VERSION 5.8 ;
BUSBITCHARS "[]" ;
DIVIDERCHAR "/" ;
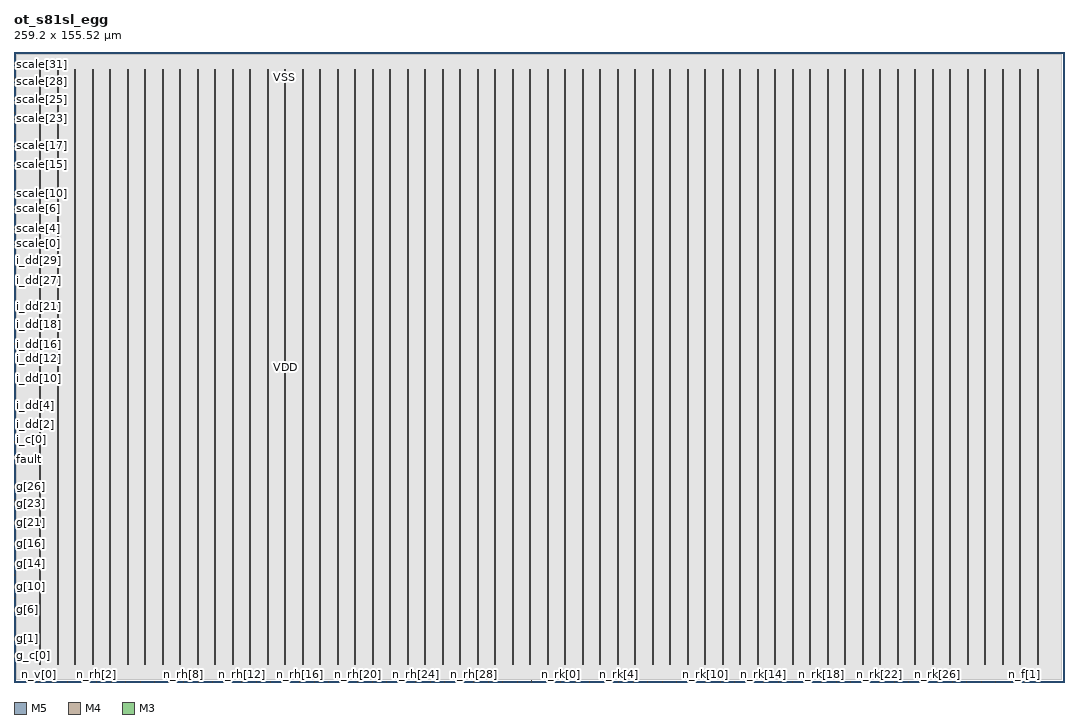
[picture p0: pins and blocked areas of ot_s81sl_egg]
MACRO ot_s81sl_egg
  CLASS BLOCK ;
  ORIGIN 0 0 ;
  FOREIGN ot_s81sl_egg 0 0 ;
  SIZE 259.200 BY 155.520 ;
  SYMMETRY X Y ;
  PIN clk
    DIRECTION INPUT ;
    USE SIGNAL ;
    PORT
      LAYER M5 ;
        RECT 127.7640 0.0000 127.8120 0.4800 ;
    END
  END clk
  PIN fault
    DIRECTION OUTPUT ;
    USE SIGNAL ;
    PORT
      LAYER M4 ;
        RECT 0.0000 54.9120 0.0840 54.9360 ;
    END
  END fault
  PIN g[0]
    DIRECTION OUTPUT ;
    USE SIGNAL ;
    PORT
      LAYER M4 ;
        RECT 0.0000 9.3120 0.0840 9.3360 ;
    END
  END g[0]
  PIN g[10]
    DIRECTION OUTPUT ;
    USE SIGNAL ;
    PORT
      LAYER M4 ;
        RECT 0.0000 23.5200 0.0840 23.5440 ;
    END
  END g[10]
  PIN g[11]
    DIRECTION OUTPUT ;
    USE SIGNAL ;
    PORT
      LAYER M4 ;
        RECT 0.0000 24.9600 0.0840 24.9840 ;
    END
  END g[11]
  PIN g[12]
    DIRECTION OUTPUT ;
    USE SIGNAL ;
    PORT
      LAYER M4 ;
        RECT 0.0000 26.4000 0.0840 26.4240 ;
    END
  END g[12]
  PIN g[13]
    DIRECTION OUTPUT ;
    USE SIGNAL ;
    PORT
      LAYER M4 ;
        RECT 0.0000 27.8400 0.0840 27.8640 ;
    END
  END g[13]
  PIN g[14]
    DIRECTION OUTPUT ;
    USE SIGNAL ;
    PORT
      LAYER M4 ;
        RECT 0.0000 29.2800 0.0840 29.3040 ;
    END
  END g[14]
  PIN g[15]
    DIRECTION OUTPUT ;
    USE SIGNAL ;
    PORT
      LAYER M4 ;
        RECT 0.0000 30.7200 0.0840 30.7440 ;
    END
  END g[15]
  PIN g[16]
    DIRECTION OUTPUT ;
    USE SIGNAL ;
    PORT
      LAYER M4 ;
        RECT 0.0000 32.1600 0.0840 32.1840 ;
    END
  END g[16]
  PIN g[17]
    DIRECTION OUTPUT ;
    USE SIGNAL ;
    PORT
      LAYER M4 ;
        RECT 0.0000 33.5040 0.0840 33.5280 ;
    END
  END g[17]
  PIN g[18]
    DIRECTION OUTPUT ;
    USE SIGNAL ;
    PORT
      LAYER M4 ;
        RECT 0.0000 34.9440 0.0840 34.9680 ;
    END
  END g[18]
  PIN g[19]
    DIRECTION OUTPUT ;
    USE SIGNAL ;
    PORT
      LAYER M4 ;
        RECT 0.0000 36.3840 0.0840 36.4080 ;
    END
  END g[19]
  PIN g[1]
    DIRECTION OUTPUT ;
    USE SIGNAL ;
    PORT
      LAYER M4 ;
        RECT 0.0000 10.7520 0.0840 10.7760 ;
    END
  END g[1]
  PIN g[20]
    DIRECTION OUTPUT ;
    USE SIGNAL ;
    PORT
      LAYER M4 ;
        RECT 0.0000 37.8240 0.0840 37.8480 ;
    END
  END g[20]
  PIN g[21]
    DIRECTION OUTPUT ;
    USE SIGNAL ;
    PORT
      LAYER M4 ;
        RECT 0.0000 39.2640 0.0840 39.2880 ;
    END
  END g[21]
  PIN g[22]
    DIRECTION OUTPUT ;
    USE SIGNAL ;
    PORT
      LAYER M4 ;
        RECT 0.0000 40.7040 0.0840 40.7280 ;
    END
  END g[22]
  PIN g[23]
    DIRECTION OUTPUT ;
    USE SIGNAL ;
    PORT
      LAYER M4 ;
        RECT 0.0000 42.1440 0.0840 42.1680 ;
    END
  END g[23]
  PIN g[24]
    DIRECTION OUTPUT ;
    USE SIGNAL ;
    PORT
      LAYER M4 ;
        RECT 0.0000 43.4880 0.0840 43.5120 ;
    END
  END g[24]
  PIN g[25]
    DIRECTION OUTPUT ;
    USE SIGNAL ;
    PORT
      LAYER M4 ;
        RECT 0.0000 44.9280 0.0840 44.9520 ;
    END
  END g[25]
  PIN g[26]
    DIRECTION OUTPUT ;
    USE SIGNAL ;
    PORT
      LAYER M4 ;
        RECT 0.0000 46.3680 0.0840 46.3920 ;
    END
  END g[26]
  PIN g[27]
    DIRECTION OUTPUT ;
    USE SIGNAL ;
    PORT
      LAYER M4 ;
        RECT 0.0000 47.8080 0.0840 47.8320 ;
    END
  END g[27]
  PIN g[28]
    DIRECTION OUTPUT ;
    USE SIGNAL ;
    PORT
      LAYER M4 ;
        RECT 0.0000 49.2480 0.0840 49.2720 ;
    END
  END g[28]
  PIN g[29]
    DIRECTION OUTPUT ;
    USE SIGNAL ;
    PORT
      LAYER M4 ;
        RECT 0.0000 50.6880 0.0840 50.7120 ;
    END
  END g[29]
  PIN g[2]
    DIRECTION OUTPUT ;
    USE SIGNAL ;
    PORT
      LAYER M4 ;
        RECT 0.0000 12.1920 0.0840 12.2160 ;
    END
  END g[2]
  PIN g[30]
    DIRECTION OUTPUT ;
    USE SIGNAL ;
    PORT
      LAYER M4 ;
        RECT 0.0000 52.0320 0.0840 52.0560 ;
    END
  END g[30]
  PIN g[31]
    DIRECTION OUTPUT ;
    USE SIGNAL ;
    PORT
      LAYER M4 ;
        RECT 0.0000 53.4720 0.0840 53.4960 ;
    END
  END g[31]
  PIN g[3]
    DIRECTION OUTPUT ;
    USE SIGNAL ;
    PORT
      LAYER M4 ;
        RECT 0.0000 13.5360 0.0840 13.5600 ;
    END
  END g[3]
  PIN g[4]
    DIRECTION OUTPUT ;
    USE SIGNAL ;
    PORT
      LAYER M4 ;
        RECT 0.0000 14.9760 0.0840 15.0000 ;
    END
  END g[4]
  PIN g[5]
    DIRECTION OUTPUT ;
    USE SIGNAL ;
    PORT
      LAYER M4 ;
        RECT 0.0000 16.4160 0.0840 16.4400 ;
    END
  END g[5]
  PIN g[6]
    DIRECTION OUTPUT ;
    USE SIGNAL ;
    PORT
      LAYER M4 ;
        RECT 0.0000 17.8560 0.0840 17.8800 ;
    END
  END g[6]
  PIN g[7]
    DIRECTION OUTPUT ;
    USE SIGNAL ;
    PORT
      LAYER M4 ;
        RECT 0.0000 19.2960 0.0840 19.3200 ;
    END
  END g[7]
  PIN g[8]
    DIRECTION OUTPUT ;
    USE SIGNAL ;
    PORT
      LAYER M4 ;
        RECT 0.0000 20.7360 0.0840 20.7600 ;
    END
  END g[8]
  PIN g[9]
    DIRECTION OUTPUT ;
    USE SIGNAL ;
    PORT
      LAYER M4 ;
        RECT 0.0000 22.1760 0.0840 22.2000 ;
    END
  END g[9]
  PIN g_c[0]
    DIRECTION OUTPUT ;
    USE SIGNAL ;
    PORT
      LAYER M4 ;
        RECT 0.0000 6.4320 0.0840 6.4560 ;
    END
  END g_c[0]
  PIN g_c[1]
    DIRECTION OUTPUT ;
    USE SIGNAL ;
    PORT
      LAYER M4 ;
        RECT 0.0000 7.8720 0.0840 7.8960 ;
    END
  END g_c[1]
  PIN g_v
    DIRECTION OUTPUT ;
    USE SIGNAL ;
    PORT
      LAYER M4 ;
        RECT 0.0000 4.9920 0.0840 5.0160 ;
    END
  END g_v
  PIN i_c[0]
    DIRECTION INPUT ;
    USE SIGNAL ;
    PORT
      LAYER M4 ;
        RECT 0.0000 57.7920 0.0840 57.8160 ;
    END
  END i_c[0]
  PIN i_c[1]
    DIRECTION INPUT ;
    USE SIGNAL ;
    PORT
      LAYER M4 ;
        RECT 0.0000 59.2320 0.0840 59.2560 ;
    END
  END i_c[1]
  PIN i_dd[0]
    DIRECTION INPUT ;
    USE SIGNAL ;
    PORT
      LAYER M4 ;
        RECT 0.0000 60.6720 0.0840 60.6960 ;
    END
  END i_dd[0]
  PIN i_dd[10]
    DIRECTION INPUT ;
    USE SIGNAL ;
    PORT
      LAYER M4 ;
        RECT 0.0000 74.8800 0.0840 74.9040 ;
    END
  END i_dd[10]
  PIN i_dd[11]
    DIRECTION INPUT ;
    USE SIGNAL ;
    PORT
      LAYER M4 ;
        RECT 0.0000 76.3200 0.0840 76.3440 ;
    END
  END i_dd[11]
  PIN i_dd[12]
    DIRECTION INPUT ;
    USE SIGNAL ;
    PORT
      LAYER M4 ;
        RECT 0.0000 77.7600 0.0840 77.7840 ;
    END
  END i_dd[12]
  PIN i_dd[13]
    DIRECTION INPUT ;
    USE SIGNAL ;
    PORT
      LAYER M4 ;
        RECT 0.0000 79.2000 0.0840 79.2240 ;
    END
  END i_dd[13]
  PIN i_dd[14]
    DIRECTION INPUT ;
    USE SIGNAL ;
    PORT
      LAYER M4 ;
        RECT 0.0000 80.6400 0.0840 80.6640 ;
    END
  END i_dd[14]
  PIN i_dd[15]
    DIRECTION INPUT ;
    USE SIGNAL ;
    PORT
      LAYER M4 ;
        RECT 0.0000 81.9840 0.0840 82.0080 ;
    END
  END i_dd[15]
  PIN i_dd[16]
    DIRECTION INPUT ;
    USE SIGNAL ;
    PORT
      LAYER M4 ;
        RECT 0.0000 83.4240 0.0840 83.4480 ;
    END
  END i_dd[16]
  PIN i_dd[17]
    DIRECTION INPUT ;
    USE SIGNAL ;
    PORT
      LAYER M4 ;
        RECT 0.0000 84.8640 0.0840 84.8880 ;
    END
  END i_dd[17]
  PIN i_dd[18]
    DIRECTION INPUT ;
    USE SIGNAL ;
    PORT
      LAYER M4 ;
        RECT 0.0000 86.3040 0.0840 86.3280 ;
    END
  END i_dd[18]
  PIN i_dd[19]
    DIRECTION INPUT ;
    USE SIGNAL ;
    PORT
      LAYER M4 ;
        RECT 0.0000 87.7440 0.0840 87.7680 ;
    END
  END i_dd[19]
  PIN i_dd[1]
    DIRECTION INPUT ;
    USE SIGNAL ;
    PORT
      LAYER M4 ;
        RECT 0.0000 62.0160 0.0840 62.0400 ;
    END
  END i_dd[1]
  PIN i_dd[20]
    DIRECTION INPUT ;
    USE SIGNAL ;
    PORT
      LAYER M4 ;
        RECT 0.0000 89.1840 0.0840 89.2080 ;
    END
  END i_dd[20]
  PIN i_dd[21]
    DIRECTION INPUT ;
    USE SIGNAL ;
    PORT
      LAYER M4 ;
        RECT 0.0000 90.6240 0.0840 90.6480 ;
    END
  END i_dd[21]
  PIN i_dd[22]
    DIRECTION INPUT ;
    USE SIGNAL ;
    PORT
      LAYER M4 ;
        RECT 0.0000 91.9680 0.0840 91.9920 ;
    END
  END i_dd[22]
  PIN i_dd[23]
    DIRECTION INPUT ;
    USE SIGNAL ;
    PORT
      LAYER M4 ;
        RECT 0.0000 93.4080 0.0840 93.4320 ;
    END
  END i_dd[23]
  PIN i_dd[24]
    DIRECTION INPUT ;
    USE SIGNAL ;
    PORT
      LAYER M4 ;
        RECT 0.0000 94.8480 0.0840 94.8720 ;
    END
  END i_dd[24]
  PIN i_dd[25]
    DIRECTION INPUT ;
    USE SIGNAL ;
    PORT
      LAYER M4 ;
        RECT 0.0000 96.2880 0.0840 96.3120 ;
    END
  END i_dd[25]
  PIN i_dd[26]
    DIRECTION INPUT ;
    USE SIGNAL ;
    PORT
      LAYER M4 ;
        RECT 0.0000 97.7280 0.0840 97.7520 ;
    END
  END i_dd[26]
  PIN i_dd[27]
    DIRECTION INPUT ;
    USE SIGNAL ;
    PORT
      LAYER M4 ;
        RECT 0.0000 99.1680 0.0840 99.1920 ;
    END
  END i_dd[27]
  PIN i_dd[28]
    DIRECTION INPUT ;
    USE SIGNAL ;
    PORT
      LAYER M4 ;
        RECT 0.0000 100.6080 0.0840 100.6320 ;
    END
  END i_dd[28]
  PIN i_dd[29]
    DIRECTION INPUT ;
    USE SIGNAL ;
    PORT
      LAYER M4 ;
        RECT 0.0000 101.9520 0.0840 101.9760 ;
    END
  END i_dd[29]
  PIN i_dd[2]
    DIRECTION INPUT ;
    USE SIGNAL ;
    PORT
      LAYER M4 ;
        RECT 0.0000 63.4560 0.0840 63.4800 ;
    END
  END i_dd[2]
  PIN i_dd[30]
    DIRECTION INPUT ;
    USE SIGNAL ;
    PORT
      LAYER M4 ;
        RECT 0.0000 103.3920 0.0840 103.4160 ;
    END
  END i_dd[30]
  PIN i_dd[31]
    DIRECTION INPUT ;
    USE SIGNAL ;
    PORT
      LAYER M4 ;
        RECT 0.0000 104.8320 0.0840 104.8560 ;
    END
  END i_dd[31]
  PIN i_dd[3]
    DIRECTION INPUT ;
    USE SIGNAL ;
    PORT
      LAYER M4 ;
        RECT 0.0000 64.8960 0.0840 64.9200 ;
    END
  END i_dd[3]
  PIN i_dd[4]
    DIRECTION INPUT ;
    USE SIGNAL ;
    PORT
      LAYER M4 ;
        RECT 0.0000 66.3360 0.0840 66.3600 ;
    END
  END i_dd[4]
  PIN i_dd[5]
    DIRECTION INPUT ;
    USE SIGNAL ;
    PORT
      LAYER M4 ;
        RECT 0.0000 67.7760 0.0840 67.8000 ;
    END
  END i_dd[5]
  PIN i_dd[6]
    DIRECTION INPUT ;
    USE SIGNAL ;
    PORT
      LAYER M4 ;
        RECT 0.0000 69.2160 0.0840 69.2400 ;
    END
  END i_dd[6]
  PIN i_dd[7]
    DIRECTION INPUT ;
    USE SIGNAL ;
    PORT
      LAYER M4 ;
        RECT 0.0000 70.6560 0.0840 70.6800 ;
    END
  END i_dd[7]
  PIN i_dd[8]
    DIRECTION INPUT ;
    USE SIGNAL ;
    PORT
      LAYER M4 ;
        RECT 0.0000 72.0000 0.0840 72.0240 ;
    END
  END i_dd[8]
  PIN i_dd[9]
    DIRECTION INPUT ;
    USE SIGNAL ;
    PORT
      LAYER M4 ;
        RECT 0.0000 73.4400 0.0840 73.4640 ;
    END
  END i_dd[9]
  PIN i_v
    DIRECTION INPUT ;
    USE SIGNAL ;
    PORT
      LAYER M4 ;
        RECT 0.0000 56.3520 0.0840 56.3760 ;
    END
  END i_v
  PIN n_f[0]
    DIRECTION INPUT ;
    USE SIGNAL ;
    PORT
      LAYER M5 ;
        RECT 9.6960 0.0000 9.7200 0.0840 ;
    END
  END n_f[0]
  PIN n_f[1]
    DIRECTION INPUT ;
    USE SIGNAL ;
    PORT
      LAYER M3 ;
        RECT 249.4800 0.0000 249.4980 0.0380 ;
    END
  END n_f[1]
  PIN n_rh[0]
    DIRECTION INPUT ;
    USE SIGNAL ;
    PORT
      LAYER M3 ;
        RECT 13.2480 0.0000 13.2660 0.0380 ;
    END
  END n_rh[0]
  PIN n_rh[10]
    DIRECTION INPUT ;
    USE SIGNAL ;
    PORT
      LAYER M3 ;
        RECT 49.0320 0.0000 49.0500 0.0380 ;
    END
  END n_rh[10]
  PIN n_rh[11]
    DIRECTION INPUT ;
    USE SIGNAL ;
    PORT
      LAYER M5 ;
        RECT 52.6080 0.0000 52.6320 0.0840 ;
    END
  END n_rh[11]
  PIN n_rh[12]
    DIRECTION INPUT ;
    USE SIGNAL ;
    PORT
      LAYER M3 ;
        RECT 56.2320 0.0000 56.2500 0.0380 ;
    END
  END n_rh[12]
  PIN n_rh[13]
    DIRECTION INPUT ;
    USE SIGNAL ;
    PORT
      LAYER M5 ;
        RECT 59.8080 0.0000 59.8320 0.0840 ;
    END
  END n_rh[13]
  PIN n_rh[14]
    DIRECTION INPUT ;
    USE SIGNAL ;
    PORT
      LAYER M3 ;
        RECT 63.3600 0.0000 63.3780 0.0380 ;
    END
  END n_rh[14]
  PIN n_rh[15]
    DIRECTION INPUT ;
    USE SIGNAL ;
    PORT
      LAYER M5 ;
        RECT 66.9120 0.0000 66.9360 0.0840 ;
    END
  END n_rh[15]
  PIN n_rh[16]
    DIRECTION INPUT ;
    USE SIGNAL ;
    PORT
      LAYER M3 ;
        RECT 70.5600 0.0000 70.5780 0.0380 ;
    END
  END n_rh[16]
  PIN n_rh[17]
    DIRECTION INPUT ;
    USE SIGNAL ;
    PORT
      LAYER M5 ;
        RECT 74.1120 0.0000 74.1360 0.0840 ;
    END
  END n_rh[17]
  PIN n_rh[18]
    DIRECTION INPUT ;
    USE SIGNAL ;
    PORT
      LAYER M3 ;
        RECT 77.6880 0.0000 77.7060 0.0380 ;
    END
  END n_rh[18]
  PIN n_rh[19]
    DIRECTION INPUT ;
    USE SIGNAL ;
    PORT
      LAYER M5 ;
        RECT 81.3120 0.0000 81.3360 0.0840 ;
    END
  END n_rh[19]
  PIN n_rh[1]
    DIRECTION INPUT ;
    USE SIGNAL ;
    PORT
      LAYER M5 ;
        RECT 16.8000 0.0000 16.8240 0.0840 ;
    END
  END n_rh[1]
  PIN n_rh[20]
    DIRECTION INPUT ;
    USE SIGNAL ;
    PORT
      LAYER M3 ;
        RECT 84.8160 0.0000 84.8340 0.0380 ;
    END
  END n_rh[20]
  PIN n_rh[21]
    DIRECTION INPUT ;
    USE SIGNAL ;
    PORT
      LAYER M5 ;
        RECT 88.4160 0.0000 88.4400 0.0840 ;
    END
  END n_rh[21]
  PIN n_rh[22]
    DIRECTION INPUT ;
    USE SIGNAL ;
    PORT
      LAYER M3 ;
        RECT 92.0160 0.0000 92.0340 0.0380 ;
    END
  END n_rh[22]
  PIN n_rh[23]
    DIRECTION INPUT ;
    USE SIGNAL ;
    PORT
      LAYER M5 ;
        RECT 95.6160 0.0000 95.6400 0.0840 ;
    END
  END n_rh[23]
  PIN n_rh[24]
    DIRECTION INPUT ;
    USE SIGNAL ;
    PORT
      LAYER M3 ;
        RECT 99.1440 0.0000 99.1620 0.0380 ;
    END
  END n_rh[24]
  PIN n_rh[25]
    DIRECTION INPUT ;
    USE SIGNAL ;
    PORT
      LAYER M5 ;
        RECT 102.7200 0.0000 102.7440 0.0840 ;
    END
  END n_rh[25]
  PIN n_rh[26]
    DIRECTION INPUT ;
    USE SIGNAL ;
    PORT
      LAYER M3 ;
        RECT 106.3440 0.0000 106.3620 0.0380 ;
    END
  END n_rh[26]
  PIN n_rh[27]
    DIRECTION INPUT ;
    USE SIGNAL ;
    PORT
      LAYER M5 ;
        RECT 109.9200 0.0000 109.9440 0.0840 ;
    END
  END n_rh[27]
  PIN n_rh[28]
    DIRECTION INPUT ;
    USE SIGNAL ;
    PORT
      LAYER M3 ;
        RECT 113.4720 0.0000 113.4900 0.0380 ;
    END
  END n_rh[28]
  PIN n_rh[29]
    DIRECTION INPUT ;
    USE SIGNAL ;
    PORT
      LAYER M5 ;
        RECT 117.0240 0.0000 117.0480 0.0840 ;
    END
  END n_rh[29]
  PIN n_rh[2]
    DIRECTION INPUT ;
    USE SIGNAL ;
    PORT
      LAYER M3 ;
        RECT 20.4480 0.0000 20.4660 0.0380 ;
    END
  END n_rh[2]
  PIN n_rh[30]
    DIRECTION INPUT ;
    USE SIGNAL ;
    PORT
      LAYER M3 ;
        RECT 120.6720 0.0000 120.6900 0.0380 ;
    END
  END n_rh[30]
  PIN n_rh[31]
    DIRECTION INPUT ;
    USE SIGNAL ;
    PORT
      LAYER M5 ;
        RECT 124.2240 0.0000 124.2480 0.0840 ;
    END
  END n_rh[31]
  PIN n_rh[3]
    DIRECTION INPUT ;
    USE SIGNAL ;
    PORT
      LAYER M5 ;
        RECT 24.0000 0.0000 24.0240 0.0840 ;
    END
  END n_rh[3]
  PIN n_rh[4]
    DIRECTION INPUT ;
    USE SIGNAL ;
    PORT
      LAYER M3 ;
        RECT 27.5760 0.0000 27.5940 0.0380 ;
    END
  END n_rh[4]
  PIN n_rh[5]
    DIRECTION INPUT ;
    USE SIGNAL ;
    PORT
      LAYER M5 ;
        RECT 31.2000 0.0000 31.2240 0.0840 ;
    END
  END n_rh[5]
  PIN n_rh[6]
    DIRECTION INPUT ;
    USE SIGNAL ;
    PORT
      LAYER M3 ;
        RECT 34.7040 0.0000 34.7220 0.0380 ;
    END
  END n_rh[6]
  PIN n_rh[7]
    DIRECTION INPUT ;
    USE SIGNAL ;
    PORT
      LAYER M5 ;
        RECT 38.3040 0.0000 38.3280 0.0840 ;
    END
  END n_rh[7]
  PIN n_rh[8]
    DIRECTION INPUT ;
    USE SIGNAL ;
    PORT
      LAYER M3 ;
        RECT 41.9040 0.0000 41.9220 0.0380 ;
    END
  END n_rh[8]
  PIN n_rh[9]
    DIRECTION INPUT ;
    USE SIGNAL ;
    PORT
      LAYER M5 ;
        RECT 45.5040 0.0000 45.5280 0.0840 ;
    END
  END n_rh[9]
  PIN n_rk[0]
    DIRECTION INPUT ;
    USE SIGNAL ;
    PORT
      LAYER M3 ;
        RECT 134.9280 0.0000 134.9460 0.0380 ;
    END
  END n_rk[0]
  PIN n_rk[10]
    DIRECTION INPUT ;
    USE SIGNAL ;
    PORT
      LAYER M3 ;
        RECT 170.7840 0.0000 170.8020 0.0380 ;
    END
  END n_rk[10]
  PIN n_rk[11]
    DIRECTION INPUT ;
    USE SIGNAL ;
    PORT
      LAYER M5 ;
        RECT 174.3360 0.0000 174.3600 0.0840 ;
    END
  END n_rk[11]
  PIN n_rk[12]
    DIRECTION INPUT ;
    USE SIGNAL ;
    PORT
      LAYER M3 ;
        RECT 177.9120 0.0000 177.9300 0.0380 ;
    END
  END n_rk[12]
  PIN n_rk[13]
    DIRECTION INPUT ;
    USE SIGNAL ;
    PORT
      LAYER M5 ;
        RECT 181.5360 0.0000 181.5600 0.0840 ;
    END
  END n_rk[13]
  PIN n_rk[14]
    DIRECTION INPUT ;
    USE SIGNAL ;
    PORT
      LAYER M3 ;
        RECT 185.0400 0.0000 185.0580 0.0380 ;
    END
  END n_rk[14]
  PIN n_rk[15]
    DIRECTION INPUT ;
    USE SIGNAL ;
    PORT
      LAYER M5 ;
        RECT 188.6400 0.0000 188.6640 0.0840 ;
    END
  END n_rk[15]
  PIN n_rk[16]
    DIRECTION INPUT ;
    USE SIGNAL ;
    PORT
      LAYER M3 ;
        RECT 192.2400 0.0000 192.2580 0.0380 ;
    END
  END n_rk[16]
  PIN n_rk[17]
    DIRECTION INPUT ;
    USE SIGNAL ;
    PORT
      LAYER M5 ;
        RECT 195.8400 0.0000 195.8640 0.0840 ;
    END
  END n_rk[17]
  PIN n_rk[18]
    DIRECTION INPUT ;
    USE SIGNAL ;
    PORT
      LAYER M3 ;
        RECT 199.3680 0.0000 199.3860 0.0380 ;
    END
  END n_rk[18]
  PIN n_rk[19]
    DIRECTION INPUT ;
    USE SIGNAL ;
    PORT
      LAYER M5 ;
        RECT 202.9440 0.0000 202.9680 0.0840 ;
    END
  END n_rk[19]
  PIN n_rk[1]
    DIRECTION INPUT ;
    USE SIGNAL ;
    PORT
      LAYER M5 ;
        RECT 138.5280 0.0000 138.5520 0.0840 ;
    END
  END n_rk[1]
  PIN n_rk[20]
    DIRECTION INPUT ;
    USE SIGNAL ;
    PORT
      LAYER M3 ;
        RECT 206.5680 0.0000 206.5860 0.0380 ;
    END
  END n_rk[20]
  PIN n_rk[21]
    DIRECTION INPUT ;
    USE SIGNAL ;
    PORT
      LAYER M5 ;
        RECT 210.1440 0.0000 210.1680 0.0840 ;
    END
  END n_rk[21]
  PIN n_rk[22]
    DIRECTION INPUT ;
    USE SIGNAL ;
    PORT
      LAYER M3 ;
        RECT 213.6960 0.0000 213.7140 0.0380 ;
    END
  END n_rk[22]
  PIN n_rk[23]
    DIRECTION INPUT ;
    USE SIGNAL ;
    PORT
      LAYER M5 ;
        RECT 217.2480 0.0000 217.2720 0.0840 ;
    END
  END n_rk[23]
  PIN n_rk[24]
    DIRECTION INPUT ;
    USE SIGNAL ;
    PORT
      LAYER M3 ;
        RECT 220.8960 0.0000 220.9140 0.0380 ;
    END
  END n_rk[24]
  PIN n_rk[25]
    DIRECTION INPUT ;
    USE SIGNAL ;
    PORT
      LAYER M5 ;
        RECT 224.4480 0.0000 224.4720 0.0840 ;
    END
  END n_rk[25]
  PIN n_rk[26]
    DIRECTION INPUT ;
    USE SIGNAL ;
    PORT
      LAYER M3 ;
        RECT 228.0240 0.0000 228.0420 0.0380 ;
    END
  END n_rk[26]
  PIN n_rk[27]
    DIRECTION INPUT ;
    USE SIGNAL ;
    PORT
      LAYER M5 ;
        RECT 231.6480 0.0000 231.6720 0.0840 ;
    END
  END n_rk[27]
  PIN n_rk[28]
    DIRECTION INPUT ;
    USE SIGNAL ;
    PORT
      LAYER M3 ;
        RECT 235.1520 0.0000 235.1700 0.0380 ;
    END
  END n_rk[28]
  PIN n_rk[29]
    DIRECTION INPUT ;
    USE SIGNAL ;
    PORT
      LAYER M5 ;
        RECT 238.7520 0.0000 238.7760 0.0840 ;
    END
  END n_rk[29]
  PIN n_rk[2]
    DIRECTION INPUT ;
    USE SIGNAL ;
    PORT
      LAYER M3 ;
        RECT 142.1280 0.0000 142.1460 0.0380 ;
    END
  END n_rk[2]
  PIN n_rk[30]
    DIRECTION INPUT ;
    USE SIGNAL ;
    PORT
      LAYER M3 ;
        RECT 242.3520 0.0000 242.3700 0.0380 ;
    END
  END n_rk[30]
  PIN n_rk[31]
    DIRECTION INPUT ;
    USE SIGNAL ;
    PORT
      LAYER M5 ;
        RECT 245.9520 0.0000 245.9760 0.0840 ;
    END
  END n_rk[31]
  PIN n_rk[3]
    DIRECTION INPUT ;
    USE SIGNAL ;
    PORT
      LAYER M5 ;
        RECT 145.7280 0.0000 145.7520 0.0840 ;
    END
  END n_rk[3]
  PIN n_rk[4]
    DIRECTION INPUT ;
    USE SIGNAL ;
    PORT
      LAYER M3 ;
        RECT 149.2560 0.0000 149.2740 0.0380 ;
    END
  END n_rk[4]
  PIN n_rk[5]
    DIRECTION INPUT ;
    USE SIGNAL ;
    PORT
      LAYER M5 ;
        RECT 152.8320 0.0000 152.8560 0.0840 ;
    END
  END n_rk[5]
  PIN n_rk[6]
    DIRECTION INPUT ;
    USE SIGNAL ;
    PORT
      LAYER M3 ;
        RECT 156.4560 0.0000 156.4740 0.0380 ;
    END
  END n_rk[6]
  PIN n_rk[7]
    DIRECTION INPUT ;
    USE SIGNAL ;
    PORT
      LAYER M5 ;
        RECT 160.0320 0.0000 160.0560 0.0840 ;
    END
  END n_rk[7]
  PIN n_rk[8]
    DIRECTION INPUT ;
    USE SIGNAL ;
    PORT
      LAYER M3 ;
        RECT 163.5840 0.0000 163.6020 0.0380 ;
    END
  END n_rk[8]
  PIN n_rk[9]
    DIRECTION INPUT ;
    USE SIGNAL ;
    PORT
      LAYER M5 ;
        RECT 167.1360 0.0000 167.1600 0.0840 ;
    END
  END n_rk[9]
  PIN n_v[0]
    DIRECTION INPUT ;
    USE SIGNAL ;
    PORT
      LAYER M3 ;
        RECT 6.1200 0.0000 6.1380 0.0380 ;
    END
  END n_v[0]
  PIN n_v[1]
    DIRECTION INPUT ;
    USE SIGNAL ;
    PORT
      LAYER M5 ;
        RECT 253.0560 0.0000 253.0800 0.0840 ;
    END
  END n_v[1]
  PIN rst_n
    DIRECTION INPUT ;
    USE SIGNAL ;
    PORT
      LAYER M5 ;
        RECT 131.4240 0.0000 131.4480 0.0840 ;
    END
  END rst_n
  PIN scale[0]
    DIRECTION INPUT ;
    USE SIGNAL ;
    PORT
      LAYER M4 ;
        RECT 0.0000 106.2720 0.0840 106.2960 ;
    END
  END scale[0]
  PIN scale[10]
    DIRECTION INPUT ;
    USE SIGNAL ;
    PORT
      LAYER M4 ;
        RECT 0.0000 120.5760 0.0840 120.6000 ;
    END
  END scale[10]
  PIN scale[11]
    DIRECTION INPUT ;
    USE SIGNAL ;
    PORT
      LAYER M4 ;
        RECT 0.0000 121.9200 0.0840 121.9440 ;
    END
  END scale[11]
  PIN scale[12]
    DIRECTION INPUT ;
    USE SIGNAL ;
    PORT
      LAYER M4 ;
        RECT 0.0000 123.3600 0.0840 123.3840 ;
    END
  END scale[12]
  PIN scale[13]
    DIRECTION INPUT ;
    USE SIGNAL ;
    PORT
      LAYER M4 ;
        RECT 0.0000 124.8000 0.0840 124.8240 ;
    END
  END scale[13]
  PIN scale[14]
    DIRECTION INPUT ;
    USE SIGNAL ;
    PORT
      LAYER M4 ;
        RECT 0.0000 126.2400 0.0840 126.2640 ;
    END
  END scale[14]
  PIN scale[15]
    DIRECTION INPUT ;
    USE SIGNAL ;
    PORT
      LAYER M4 ;
        RECT 0.0000 127.6800 0.0840 127.7040 ;
    END
  END scale[15]
  PIN scale[16]
    DIRECTION INPUT ;
    USE SIGNAL ;
    PORT
      LAYER M4 ;
        RECT 0.0000 129.1200 0.0840 129.1440 ;
    END
  END scale[16]
  PIN scale[17]
    DIRECTION INPUT ;
    USE SIGNAL ;
    PORT
      LAYER M4 ;
        RECT 0.0000 130.4640 0.0840 130.4880 ;
    END
  END scale[17]
  PIN scale[18]
    DIRECTION INPUT ;
    USE SIGNAL ;
    PORT
      LAYER M4 ;
        RECT 0.0000 131.9040 0.0840 131.9280 ;
    END
  END scale[18]
  PIN scale[19]
    DIRECTION INPUT ;
    USE SIGNAL ;
    PORT
      LAYER M4 ;
        RECT 0.0000 133.3440 0.0840 133.3680 ;
    END
  END scale[19]
  PIN scale[1]
    DIRECTION INPUT ;
    USE SIGNAL ;
    PORT
      LAYER M4 ;
        RECT 0.0000 107.7120 0.0840 107.7360 ;
    END
  END scale[1]
  PIN scale[20]
    DIRECTION INPUT ;
    USE SIGNAL ;
    PORT
      LAYER M4 ;
        RECT 0.0000 134.7840 0.0840 134.8080 ;
    END
  END scale[20]
  PIN scale[21]
    DIRECTION INPUT ;
    USE SIGNAL ;
    PORT
      LAYER M4 ;
        RECT 0.0000 136.2240 0.0840 136.2480 ;
    END
  END scale[21]
  PIN scale[22]
    DIRECTION INPUT ;
    USE SIGNAL ;
    PORT
      LAYER M4 ;
        RECT 0.0000 137.6640 0.0840 137.6880 ;
    END
  END scale[22]
  PIN scale[23]
    DIRECTION INPUT ;
    USE SIGNAL ;
    PORT
      LAYER M4 ;
        RECT 0.0000 139.1040 0.0840 139.1280 ;
    END
  END scale[23]
  PIN scale[24]
    DIRECTION INPUT ;
    USE SIGNAL ;
    PORT
      LAYER M4 ;
        RECT 0.0000 140.4480 0.0840 140.4720 ;
    END
  END scale[24]
  PIN scale[25]
    DIRECTION INPUT ;
    USE SIGNAL ;
    PORT
      LAYER M4 ;
        RECT 0.0000 141.8880 0.0840 141.9120 ;
    END
  END scale[25]
  PIN scale[26]
    DIRECTION INPUT ;
    USE SIGNAL ;
    PORT
      LAYER M4 ;
        RECT 0.0000 143.3280 0.0840 143.3520 ;
    END
  END scale[26]
  PIN scale[27]
    DIRECTION INPUT ;
    USE SIGNAL ;
    PORT
      LAYER M4 ;
        RECT 0.0000 144.7680 0.0840 144.7920 ;
    END
  END scale[27]
  PIN scale[28]
    DIRECTION INPUT ;
    USE SIGNAL ;
    PORT
      LAYER M4 ;
        RECT 0.0000 146.2080 0.0840 146.2320 ;
    END
  END scale[28]
  PIN scale[29]
    DIRECTION INPUT ;
    USE SIGNAL ;
    PORT
      LAYER M4 ;
        RECT 0.0000 147.6480 0.0840 147.6720 ;
    END
  END scale[29]
  PIN scale[2]
    DIRECTION INPUT ;
    USE SIGNAL ;
    PORT
      LAYER M4 ;
        RECT 0.0000 109.1520 0.0840 109.1760 ;
    END
  END scale[2]
  PIN scale[30]
    DIRECTION INPUT ;
    USE SIGNAL ;
    PORT
      LAYER M4 ;
        RECT 0.0000 149.0880 0.0840 149.1120 ;
    END
  END scale[30]
  PIN scale[31]
    DIRECTION INPUT ;
    USE SIGNAL ;
    PORT
      LAYER M4 ;
        RECT 0.0000 150.4320 0.0840 150.4560 ;
    END
  END scale[31]
  PIN scale[3]
    DIRECTION INPUT ;
    USE SIGNAL ;
    PORT
      LAYER M4 ;
        RECT 0.0000 110.5920 0.0840 110.6160 ;
    END
  END scale[3]
  PIN scale[4]
    DIRECTION INPUT ;
    USE SIGNAL ;
    PORT
      LAYER M4 ;
        RECT 0.0000 111.9360 0.0840 111.9600 ;
    END
  END scale[4]
  PIN scale[5]
    DIRECTION INPUT ;
    USE SIGNAL ;
    PORT
      LAYER M4 ;
        RECT 0.0000 113.3760 0.0840 113.4000 ;
    END
  END scale[5]
  PIN scale[6]
    DIRECTION INPUT ;
    USE SIGNAL ;
    PORT
      LAYER M4 ;
        RECT 0.0000 114.8160 0.0840 114.8400 ;
    END
  END scale[6]
  PIN scale[7]
    DIRECTION INPUT ;
    USE SIGNAL ;
    PORT
      LAYER M4 ;
        RECT 0.0000 116.2560 0.0840 116.2800 ;
    END
  END scale[7]
  PIN scale[8]
    DIRECTION INPUT ;
    USE SIGNAL ;
    PORT
      LAYER M4 ;
        RECT 0.0000 117.6960 0.0840 117.7200 ;
    END
  END scale[8]
  PIN scale[9]
    DIRECTION INPUT ;
    USE SIGNAL ;
    PORT
      LAYER M4 ;
        RECT 0.0000 119.1360 0.0840 119.1600 ;
    END
  END scale[9]
  PIN VSS
    DIRECTION INOUT ;
    USE GROUND ;
    PORT
      LAYER M5 ;
        RECT 6.324000 4.320000 6.444000 151.200000 ;
        RECT 10.644000 4.320000 10.764000 151.200000 ;
        RECT 14.964000 4.320000 15.084000 151.200000 ;
        RECT 19.284000 4.320000 19.404000 151.200000 ;
        RECT 23.604000 4.320000 23.724000 151.200000 ;
        RECT 27.924000 4.320000 28.044000 151.200000 ;
        RECT 32.244000 4.320000 32.364000 151.200000 ;
        RECT 36.564000 4.320000 36.684000 151.200000 ;
        RECT 40.884000 4.320000 41.004000 151.200000 ;
        RECT 45.204000 4.320000 45.324000 151.200000 ;
        RECT 49.524000 4.320000 49.644000 151.200000 ;
        RECT 53.844000 4.320000 53.964000 151.200000 ;
        RECT 58.164000 4.320000 58.284000 151.200000 ;
        RECT 62.484000 4.320000 62.604000 151.200000 ;
        RECT 66.804000 4.320000 66.924000 151.200000 ;
        RECT 71.124000 4.320000 71.244000 151.200000 ;
        RECT 75.444000 4.320000 75.564000 151.200000 ;
        RECT 79.764000 4.320000 79.884000 151.200000 ;
        RECT 84.084000 4.320000 84.204000 151.200000 ;
        RECT 88.404000 4.320000 88.524000 151.200000 ;
        RECT 92.724000 4.320000 92.844000 151.200000 ;
        RECT 97.044000 4.320000 97.164000 151.200000 ;
        RECT 101.364000 4.320000 101.484000 151.200000 ;
        RECT 105.684000 4.320000 105.804000 151.200000 ;
        RECT 110.004000 4.320000 110.124000 151.200000 ;
        RECT 114.324000 4.320000 114.444000 151.200000 ;
        RECT 118.644000 4.320000 118.764000 151.200000 ;
        RECT 122.964000 4.320000 123.084000 151.200000 ;
        RECT 127.284000 4.320000 127.404000 151.200000 ;
        RECT 131.604000 4.320000 131.724000 151.200000 ;
        RECT 135.924000 4.320000 136.044000 151.200000 ;
        RECT 140.244000 4.320000 140.364000 151.200000 ;
        RECT 144.564000 4.320000 144.684000 151.200000 ;
        RECT 148.884000 4.320000 149.004000 151.200000 ;
        RECT 153.204000 4.320000 153.324000 151.200000 ;
        RECT 157.524000 4.320000 157.644000 151.200000 ;
        RECT 161.844000 4.320000 161.964000 151.200000 ;
        RECT 166.164000 4.320000 166.284000 151.200000 ;
        RECT 170.484000 4.320000 170.604000 151.200000 ;
        RECT 174.804000 4.320000 174.924000 151.200000 ;
        RECT 179.124000 4.320000 179.244000 151.200000 ;
        RECT 183.444000 4.320000 183.564000 151.200000 ;
        RECT 187.764000 4.320000 187.884000 151.200000 ;
        RECT 192.084000 4.320000 192.204000 151.200000 ;
        RECT 196.404000 4.320000 196.524000 151.200000 ;
        RECT 200.724000 4.320000 200.844000 151.200000 ;
        RECT 205.044000 4.320000 205.164000 151.200000 ;
        RECT 209.364000 4.320000 209.484000 151.200000 ;
        RECT 213.684000 4.320000 213.804000 151.200000 ;
        RECT 218.004000 4.320000 218.124000 151.200000 ;
        RECT 222.324000 4.320000 222.444000 151.200000 ;
        RECT 226.644000 4.320000 226.764000 151.200000 ;
        RECT 230.964000 4.320000 231.084000 151.200000 ;
        RECT 235.284000 4.320000 235.404000 151.200000 ;
        RECT 239.604000 4.320000 239.724000 151.200000 ;
        RECT 243.924000 4.320000 244.044000 151.200000 ;
        RECT 248.244000 4.320000 248.364000 151.200000 ;
        RECT 252.564000 4.320000 252.684000 151.200000 ;
    END
  END VSS
  PIN VDD
    DIRECTION INOUT ;
    USE POWER ;
    PORT
      LAYER M5 ;
        RECT 6.516000 4.320000 6.636000 151.200000 ;
        RECT 10.836000 4.320000 10.956000 151.200000 ;
        RECT 15.156000 4.320000 15.276000 151.200000 ;
        RECT 19.476000 4.320000 19.596000 151.200000 ;
        RECT 23.796000 4.320000 23.916000 151.200000 ;
        RECT 28.116000 4.320000 28.236000 151.200000 ;
        RECT 32.436000 4.320000 32.556000 151.200000 ;
        RECT 36.756000 4.320000 36.876000 151.200000 ;
        RECT 41.076000 4.320000 41.196000 151.200000 ;
        RECT 45.396000 4.320000 45.516000 151.200000 ;
        RECT 49.716000 4.320000 49.836000 151.200000 ;
        RECT 54.036000 4.320000 54.156000 151.200000 ;
        RECT 58.356000 4.320000 58.476000 151.200000 ;
        RECT 62.676000 4.320000 62.796000 151.200000 ;
        RECT 66.996000 4.320000 67.116000 151.200000 ;
        RECT 71.316000 4.320000 71.436000 151.200000 ;
        RECT 75.636000 4.320000 75.756000 151.200000 ;
        RECT 79.956000 4.320000 80.076000 151.200000 ;
        RECT 84.276000 4.320000 84.396000 151.200000 ;
        RECT 88.596000 4.320000 88.716000 151.200000 ;
        RECT 92.916000 4.320000 93.036000 151.200000 ;
        RECT 97.236000 4.320000 97.356000 151.200000 ;
        RECT 101.556000 4.320000 101.676000 151.200000 ;
        RECT 105.876000 4.320000 105.996000 151.200000 ;
        RECT 110.196000 4.320000 110.316000 151.200000 ;
        RECT 114.516000 4.320000 114.636000 151.200000 ;
        RECT 118.836000 4.320000 118.956000 151.200000 ;
        RECT 123.156000 4.320000 123.276000 151.200000 ;
        RECT 127.476000 4.320000 127.596000 151.200000 ;
        RECT 131.796000 4.320000 131.916000 151.200000 ;
        RECT 136.116000 4.320000 136.236000 151.200000 ;
        RECT 140.436000 4.320000 140.556000 151.200000 ;
        RECT 144.756000 4.320000 144.876000 151.200000 ;
        RECT 149.076000 4.320000 149.196000 151.200000 ;
        RECT 153.396000 4.320000 153.516000 151.200000 ;
        RECT 157.716000 4.320000 157.836000 151.200000 ;
        RECT 162.036000 4.320000 162.156000 151.200000 ;
        RECT 166.356000 4.320000 166.476000 151.200000 ;
        RECT 170.676000 4.320000 170.796000 151.200000 ;
        RECT 174.996000 4.320000 175.116000 151.200000 ;
        RECT 179.316000 4.320000 179.436000 151.200000 ;
        RECT 183.636000 4.320000 183.756000 151.200000 ;
        RECT 187.956000 4.320000 188.076000 151.200000 ;
        RECT 192.276000 4.320000 192.396000 151.200000 ;
        RECT 196.596000 4.320000 196.716000 151.200000 ;
        RECT 200.916000 4.320000 201.036000 151.200000 ;
        RECT 205.236000 4.320000 205.356000 151.200000 ;
        RECT 209.556000 4.320000 209.676000 151.200000 ;
        RECT 213.876000 4.320000 213.996000 151.200000 ;
        RECT 218.196000 4.320000 218.316000 151.200000 ;
        RECT 222.516000 4.320000 222.636000 151.200000 ;
        RECT 226.836000 4.320000 226.956000 151.200000 ;
        RECT 231.156000 4.320000 231.276000 151.200000 ;
        RECT 235.476000 4.320000 235.596000 151.200000 ;
        RECT 239.796000 4.320000 239.916000 151.200000 ;
        RECT 244.116000 4.320000 244.236000 151.200000 ;
        RECT 248.436000 4.320000 248.556000 151.200000 ;
        RECT 252.756000 4.320000 252.876000 151.200000 ;
    END
  END VDD
  OBS
    LAYER M1 ;
      RECT 0.5 0.5 258.700 155.020 ;
    LAYER M2 ;
      RECT 0.5 0.5 258.700 155.020 ;
    LAYER M3 ;
      RECT 0.5 0.5 258.700 155.020 ;
    LAYER M4 ;
      RECT 0.5 0.5 258.700 155.020 ;
    LAYER M5 ;
      RECT 0.5 0.5 258.700 155.020 ;
    LAYER M6 ;
      RECT 0.5 0.5 258.700 155.020 ;
    LAYER M7 ;
      RECT 0.5 0.5 258.700 155.020 ;
  END
END ot_s81sl_egg
END LIBRARY
